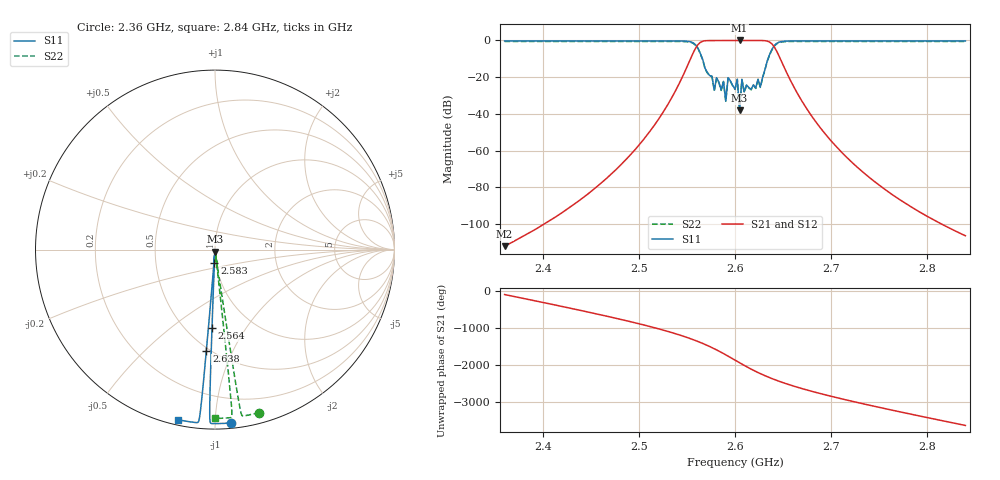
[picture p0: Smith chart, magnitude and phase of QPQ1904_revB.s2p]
! written by passband
# GHZ S DB R 50
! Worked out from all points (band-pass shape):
!   201 points, 2.36 GHz to 2.84 GHz, reference 50 ohm
!   highest |S21| = 0.00 dB at 2.605 GHz (marker M1); lowest = -112.0 dB at 2.36 GHz (marker M2)
!   |S21| within 3 dB of the highest: 2.56 GHz to 2.64 GHz (79.68 MHz wide, 3.06 % of centre)
!   lowest |S11| = -38.1 dB at 2.605 GHz (marker M3), VSWR 1.03, Z = 49.9 - j1.24 ohm
!   |S11| at or under -10 dB: 2.566 GHz to 2.634 GHz (68.28 MHz wide, 2.63 % of centre)
!   |S22| runs from -38.4 to -0.5 dB; largest |S21 - S12| = 0
!   S11 on the Smith chart (normalised r, x): 2.36 GHz: 0.03, -1.09; 2.564 GHz: 0.66, -0.71; 2.583 GHz: 0.98, -0.14; 2.638 GHz: 0.48, -0.80; 2.84 GHz: 0.03, -0.81
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2.36  -0.27 -84.9  -111.99 -104.7  -111.99 -104.7  -0.53 -74.9
2.4416  -0.27 -87.8  -85.63 173.1  -85.63 173.1  -0.53 -77.5
2.5208  -0.27 -90.7  -42.51 47.2  -42.51 47.2  -0.53 -80.0
2.5544  -0.84 -91.9  -9.09 136.8  -9.09 136.8  -1.10 -81.1
2.564  -7.16 -92.2  -0.99 41.0  -0.99 41.0  -7.43 -81.4
2.5688  -15.15 -92.4  -0.14 -11.5  -0.14 -11.5  -15.41 -81.5
2.576  -19.41 -92.6  -0.05 -96.9  -0.05 -96.9  -19.67 -81.8
2.5832  -22.70 -92.9  -0.02 169.4  -0.02 169.4  -22.97 -82.0
2.5904  -32.86 -93.2  -0.00 68.0  -0.00 68.0  -33.13 -82.2
2.5952  -22.01 -93.3  -0.03 -2.8  -0.03 -2.8  -22.27 -82.4
2.6  -26.36 -93.5  -0.01 -74.8  -0.01 -74.8  -26.62 -82.5
2.6048  -38.12 -93.7  -0.00 -146.7  -0.00 -146.7  -38.39 -82.7
2.6072  -21.13 -93.8  -0.04 177.8  -0.04 177.8  -21.40 -82.7
2.612  -24.23 -93.9  -0.02 108.4  -0.02 108.4  -24.49 -82.9
2.6192  -24.12 -94.2  -0.02 10.0  -0.02 10.0  -24.38 -83.1
2.6264  -25.29 -94.4  -0.01 -80.2  -0.01 -80.2  -25.55 -83.4
2.6336  -11.13 -94.7  -0.37 -162.2  -0.37 -162.2  -11.40 -83.6
2.6384  -4.92 -94.9  -1.82 147.3  -1.82 147.3  -5.19 -83.7
2.648  -0.63 -95.2  -10.93 55.0  -10.93 55.0  -0.90 -84.0
2.6816  -0.27 -96.4  -42.44 151.4  -42.44 151.4  -0.53 -85.1
2.7608  -0.27 -99.3  -82.82 29.7  -82.82 29.7  -0.53 -87.6
2.84  -0.27 -102.1  -106.32 -38.9  -106.32 -38.9  -0.53 -90.1
